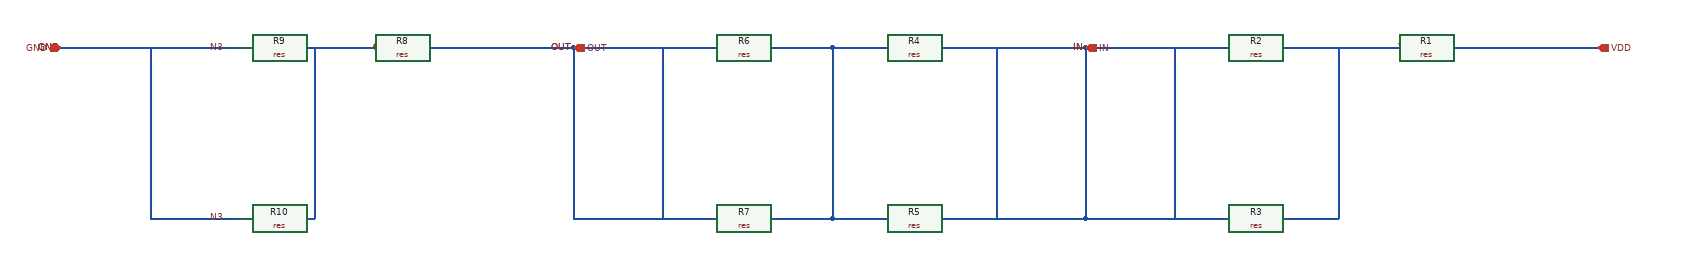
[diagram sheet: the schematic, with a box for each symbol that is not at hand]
v {xschem version=2.9.7 file_version=1.1}
G {}
V {}
S {}
E {}
N 2240 250 2500 250 {lab=VDD}
C {devices/lab_wire.sym} 2240 250 0 0 {lab=VDD}
N 1990 250 2260 250 {lab=N1}
C {devices/lab_wire.sym} 1990 250 0 0 {lab=N1}
N 1990 500 2120 500 {lab=N1}
N 2120 500 2120 250 {lab=N1}
N 2120 250 2260 250 {lab=N1}
C {devices/lab_wire.sym} 1990 500 0 0 {lab=N1}
N 1490 250 2010 250 {lab=IN}
C {devices/lab_wire.sym} 1490 250 0 0 {lab=IN}
N 1490 500 1750 500 {lab=IN}
N 1750 500 1750 250 {lab=IN}
N 1750 250 2010 250 {lab=IN}
C {devices/lab_wire.sym} 1490 500 0 0 {lab=IN}
N 1750 250 2010 250 {lab=IN}
C {devices/lab_wire.sym} 1750 250 0 0 {lab=IN}
N 1490 250 1750 250 {lab=IN}
N 1750 250 1750 500 {lab=IN}
N 1750 500 2010 500 {lab=IN}
C {devices/lab_wire.sym} 1490 250 0 0 {lab=IN}
N 1490 500 2010 500 {lab=IN}
C {devices/lab_wire.sym} 1490 500 0 0 {lab=IN}
N 1750 250 1880 250 {lab=IN}
N 1880 250 1880 500 {lab=IN}
N 1880 500 2010 500 {lab=IN}
C {devices/lab_wire.sym} 1750 250 0 0 {lab=IN}
N 1490 250 1750 250 {lab=IN}
C {devices/lab_wire.sym} 1490 250 0 0 {lab=IN}
N 1490 500 1620 500 {lab=IN}
N 1620 500 1620 250 {lab=IN}
N 1620 250 1750 250 {lab=IN}
C {devices/lab_wire.sym} 1490 500 0 0 {lab=IN}
N 1240 250 1510 250 {lab=N2}
C {devices/lab_wire.sym} 1240 250 0 0 {lab=N2}
N 1240 500 1380 500 {lab=N2}
N 1380 500 1380 250 {lab=N2}
N 1380 250 1510 250 {lab=N2}
C {devices/lab_wire.sym} 1240 500 0 0 {lab=N2}
N 1240 250 1380 250 {lab=N2}
N 1380 250 1380 500 {lab=N2}
N 1380 500 1510 500 {lab=N2}
C {devices/lab_wire.sym} 1240 250 0 0 {lab=N2}
N 1240 500 1510 500 {lab=N2}
C {devices/lab_wire.sym} 1240 500 0 0 {lab=N2}
N 740 250 1260 250 {lab=OUT}
C {devices/lab_wire.sym} 740 250 0 0 {lab=OUT}
N 1000 250 1260 250 {lab=OUT}
C {devices/lab_wire.sym} 1000 250 0 0 {lab=OUT}
N 740 250 1000 250 {lab=OUT}
N 1000 250 1000 500 {lab=OUT}
N 1000 500 1260 500 {lab=OUT}
C {devices/lab_wire.sym} 740 250 0 0 {lab=OUT}
N 1000 250 1130 250 {lab=OUT}
N 1130 250 1130 500 {lab=OUT}
N 1130 500 1260 500 {lab=OUT}
C {devices/lab_wire.sym} 1000 250 0 0 {lab=OUT}
N 740 250 1000 250 {lab=OUT}
C {devices/lab_wire.sym} 740 250 0 0 {lab=OUT}
N 490 250 760 250 {lab=N3}
C {devices/lab_wire.sym} 490 250 0 0 {lab=N3}
N 490 500 620 500 {lab=N3}
N 620 500 620 250 {lab=N3}
N 620 250 760 250 {lab=N3}
C {devices/lab_wire.sym} 490 500 0 0 {lab=N3}
N 250 250 510 250 {lab=GND}
C {devices/lab_wire.sym} 250 250 0 0 {lab=GND}
N 250 250 380 250 {lab=GND}
N 380 250 380 500 {lab=GND}
N 380 500 510 500 {lab=GND}
C {devices/lab_wire.sym} 250 250 0 0 {lab=GND}
C {devices/res.sym} 2250 250 0 0 {name=R1 value=1k}
C {devices/res.sym} 2000 250 0 0 {name=R2 value=2k}
C {devices/res.sym} 2000 500 0 0 {name=R3 value=3k}
C {devices/res.sym} 1500 250 0 0 {name=R4 value=4k}
C {devices/res.sym} 1500 500 0 0 {name=R5 value=5k}
C {devices/res.sym} 1250 250 0 0 {name=R6 value=6k}
C {devices/res.sym} 1250 500 0 0 {name=R7 value=7k}
C {devices/res.sym} 750 250 0 0 {name=R8 value=8k}
C {devices/res.sym} 500 250 0 0 {name=R9 value=9k}
C {devices/res.sym} 500 500 0 0 {name=R10 value=10k}
C {devices/opin.sym} 1750 250 0 0 {lab=IN}
C {devices/opin.sym} 1000 250 0 0 {lab=OUT}
C {devices/opin.sym} 2500 250 0 0 {lab=VDD}
C {devices/ipin.sym} 250 250 0 0 {lab=GND}
